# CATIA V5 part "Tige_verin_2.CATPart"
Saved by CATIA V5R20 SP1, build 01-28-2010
Part number: Tige_verin_2
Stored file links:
  C:\Users\MARLENE\Documents\IFMA\S3\IAO\Copie de CAO\Tige_verin_2.CATPart

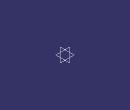
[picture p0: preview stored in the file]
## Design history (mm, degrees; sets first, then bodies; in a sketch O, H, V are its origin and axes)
Body1 (main body)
